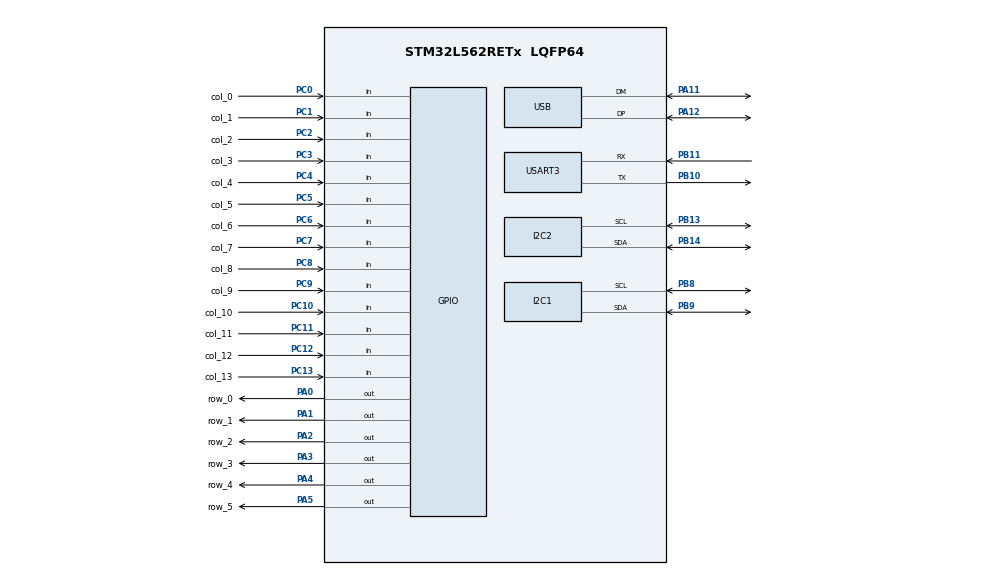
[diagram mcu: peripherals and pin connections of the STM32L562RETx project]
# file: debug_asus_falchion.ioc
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I2C1.Timing=0x10B0DCFB
I2C2.Timing=0x10B0DCFB
Mcu.Family=STM32L5
Mcu.Name=STM32L562RETx
Mcu.Package=LQFP64
NVIC.PriorityGroup=NVIC_PRIORITYGROUP_3
NVIC.USB_FS_IRQn=true\:0\:0\:false\:false\:true\:false\:true\:true
PA0.GPIO_Label=row_0
PA0.Signal=GPIO_Output
PA1.GPIO_Label=row_1
PA1.Signal=GPIO_Output
PA11.Mode=Device
PA11.Signal=USB_DM
PA12.Mode=Device
PA12.Signal=USB_DP
PA13\ (JTMS/SWDIO).Mode=Serial_Wire
PA13\ (JTMS/SWDIO).Signal=DEBUG_JTMS-SWDIO
PA14\ (JTCK/SWCLK).Mode=Serial_Wire
PA14\ (JTCK/SWCLK).Signal=DEBUG_JTCK-SWCLK
PA2.GPIO_Label=row_2
PA2.Signal=GPIO_Output
PA3.GPIO_Label=row_3
PA3.Signal=GPIO_Output
PA4.GPIO_Label=row_4
PA4.Signal=GPIO_Output
PA5.GPIO_Label=row_5
PA5.Signal=GPIO_Output
PB10.Mode=Asynchronous
PB10.Signal=USART3_TX
PB11.Mode=Asynchronous
PB11.Signal=USART3_RX
PB12.GPIO_Label=matrix
PB12.Signal=EVENTOUT
PB13.Mode=I2C
PB13.Signal=I2C2_SCL
PB14.Mode=I2C
PB14.Signal=I2C2_SDA
PB8.Mode=I2C
PB8.Signal=I2C1_SCL
PB9.Mode=I2C
PB9.Signal=I2C1_SDA
PC0.GPIO_Label=col_0
PC0.Signal=GPIO_Input
PC1.GPIO_Label=col_1
PC1.Signal=GPIO_Input
PC10.GPIO_Label=col_10
PC10.Signal=GPIO_Input
PC11.GPIO_Label=col_11
PC11.Signal=GPIO_Input
PC12.GPIO_Label=col_12
PC12.Signal=GPIO_Input
PC13.GPIO_Label=col_13
PC13.Signal=GPIO_Input
PC15-OSC32_OUT\ (PC15).GPIO_Label=reset radio
PC15-OSC32_OUT\ (PC15).Signal=EVENTOUT
PC2.GPIO_Label=col_2
PC2.Signal=GPIO_Input
PC3.GPIO_Label=col_3
PC3.Signal=GPIO_Input
PC4.GPIO_Label=col_4
PC4.Signal=GPIO_Input
PC5.GPIO_Label=col_5
PC5.Signal=GPIO_Input
PC6.GPIO_Label=col_6
PC6.Signal=GPIO_Input
PC7.GPIO_Label=col_7
PC7.Signal=GPIO_Input
PC8.GPIO_Label=col_8
PC8.Signal=GPIO_Input
PC9.GPIO_Label=col_9
PC9.Signal=GPIO_Input
PH0-OSC_IN\ (PH0).Mode=HSE-External-Oscillator
PH0-OSC_IN\ (PH0).Signal=RCC_OSC_IN
PH1-OSC_OUT\ (PH1).Mode=HSE-External-Oscillator
PH1-OSC_OUT\ (PH1).Signal=RCC_OSC_OUT
ProjectManager.HeapSize=0x200
ProjectManager.StackSize=0x4000
ProjectManager.TargetToolchain=Makefile
RCC.ADCFreq_Value=48000000
RCC.AHBFreq_Value=96000000
RCC.APB1Freq_Value=96000000
RCC.APB1TimFreq_Value=96000000
RCC.APB2Freq_Value=96000000
RCC.APB2TimFreq_Value=96000000
RCC.CortexFreq_Value=96000000
RCC.HCLKFreq_Value=96000000
RCC.HSE_VALUE=32000000
RCC.HSI48_VALUE=48000000
RCC.HSI_VALUE=16000000
RCC.LSE_VALUE=32768
RCC.MSI_VALUE=4000000
RCC.PLLM=2
RCC.PLLN=12
RCC.PLLSAI1M=4
RCC.PLLSAI1N=12
RCC.PLLSAI1Source=RCC_PLLSAI1SOURCE_HSE
RCC.PLLSourceVirtual=RCC_PLLSOURCE_HSE
RCC.SYSCLKFreq_VALUE=96000000
RCC.SYSCLKSource=RCC_SYSCLKSOURCE_PLLCLK
RCC.USBFreq_Value=48000000
RCC.VCOOutputFreq_Value=192000000
USART3.VirtualMode-Asynchronous=VM_ASYNC
USB_DEVICE.CLASS_NAME_FS=CDC
USB_DEVICE.VirtualMode=Cdc
USB_DEVICE.VirtualModeFS=Cdc_FS
VP_ICACHE_VS_ICACHE.Mode=DirectMappedCache
VP_PWR_VS_DBSignals.Mode=DisableDeadBatterySignals
VP_PWR_VS_SECSignals.Mode=Security/Privilege
VP_USB_DEVICE_VS_USB_DEVICE_CDC_FS.Mode=CDC_FS
board=custom

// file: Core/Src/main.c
/* USER CODE BEGIN Header */
/**
  ******************************************************************************
  * @file           : main.c
  * @brief          : Main program body
  ******************************************************************************
  * @attention
  *
  * Copyright (c) 2023 STMicroelectronics.
  * All rights reserved.
  *
  * This software is licensed under terms that can be found in the LICENSE file
  * in the root directory of this software component.
  * If no LICENSE file comes with this software, it is provided AS-IS.
  *
  ******************************************************************************
  */
/* USER CODE END Header */
#include "main.h"
#include "usb_device.h"

I2C_HandleTypeDef hi2c1;
I2C_HandleTypeDef hi2c2;

UART_HandleTypeDef huart3;

void SystemClock_Config(void);
static void MX_GPIO_Init(void);
static void MX_I2C1_Init(void);
static void MX_I2C2_Init(void);
static void MX_USART3_UART_Init(void);
static void MX_ICACHE_Init(void);

/* USER CODE BEGIN 0 */
int _write(int file, char *ptr, int len) {
    static uint8_t rc = USBD_OK;

    do {
        rc = CDC_Transmit_FS((uint8_t*)ptr, len);
    } while (USBD_BUSY == rc);

    if (USBD_FAIL == rc) {
        /// NOTE: Should never reach here.
        /// TODO: Handle this error.
        return 0;
    }
    return len;
}

// int fputc(int ch, FILE *f)
// {
//     if(ch == '\n') {
//       uint8_t ret = '\r';
//       CDC_Transmit_FS(&ret, 1);
//     }
//     CDC_Transmit_FS((uint8_t*)&ch, 1);
//     return ch;
// }

/* USER CODE END 0 */

int main(void)
{

  /* MCU Configuration--------------------------------------------------------*/

  /* Reset of all peripherals, Initializes the Flash interface and the Systick. */
  HAL_Init();

  /* Configure the system clock */
  SystemClock_Config();

  /* Initialize all configured peripherals */
  MX_GPIO_Init();
  MX_I2C1_Init();
  MX_I2C2_Init();
  MX_USART3_UART_Init();
  MX_ICACHE_Init();
  MX_USB_Device_Init();
  /* USER CODE BEGIN 2 */
  HAL_Delay(2000);

  printf("\r\nStart !\r\n");
  IS31FL3737_init(161);
  IS31FL3737_init(191);

  shell_start();
  /* USER CODE END 2 */

  /* Infinite loop */
  while (1)
  {

    /* USER CODE BEGIN 3 */
    //printf("[main]Hello World! \r\n");
    printf("Hello World!\r\n");
    HAL_Delay(1000);
  }
  /* USER CODE END 3 */
}

void SystemClock_Config(void)
{
  RCC_OscInitTypeDef RCC_OscInitStruct = {0};
  RCC_ClkInitTypeDef RCC_ClkInitStruct = {0};

  /** Configure the main internal regulator output voltage
  */
  if (HAL_PWREx_ControlVoltageScaling(PWR_REGULATOR_VOLTAGE_SCALE1) != HAL_OK)
  {
    Error_Handler();
  }

  /** Initializes the RCC Oscillators according to the specified parameters
  * in the RCC_OscInitTypeDef structure.
  */
  RCC_OscInitStruct.OscillatorType = RCC_OSCILLATORTYPE_HSI|RCC_OSCILLATORTYPE_HSE;
  RCC_OscInitStruct.HSEState = RCC_HSE_ON;
  RCC_OscInitStruct.HSIState = RCC_HSI_ON;
  RCC_OscInitStruct.HSICalibrationValue = RCC_HSICALIBRATION_DEFAULT;
  RCC_OscInitStruct.PLL.PLLState = RCC_PLL_ON;
  RCC_OscInitStruct.PLL.PLLSource = RCC_PLLSOURCE_HSE;
  RCC_OscInitStruct.PLL.PLLM = 2;
  RCC_OscInitStruct.PLL.PLLN = 10;
  RCC_OscInitStruct.PLL.PLLP = RCC_PLLP_DIV7;
  RCC_OscInitStruct.PLL.PLLQ = RCC_PLLQ_DIV2;
  RCC_OscInitStruct.PLL.PLLR = RCC_PLLR_DIV2;
  if (HAL_RCC_OscConfig(&RCC_OscInitStruct) != HAL_OK)
  {
    Error_Handler();
  }

  /** Initializes the CPU, AHB and APB buses clocks
  */
  RCC_ClkInitStruct.ClockType = RCC_CLOCKTYPE_HCLK|RCC_CLOCKTYPE_SYSCLK
                              |RCC_CLOCKTYPE_PCLK1|RCC_CLOCKTYPE_PCLK2;
  RCC_ClkInitStruct.SYSCLKSource = RCC_SYSCLKSOURCE_PLLCLK;
  RCC_ClkInitStruct.AHBCLKDivider = RCC_SYSCLK_DIV1;
  RCC_ClkInitStruct.APB1CLKDivider = RCC_HCLK_DIV1;
  RCC_ClkInitStruct.APB2CLKDivider = RCC_HCLK_DIV1;

  if (HAL_RCC_ClockConfig(&RCC_ClkInitStruct, FLASH_LATENCY_3) != HAL_OK)
  {
    Error_Handler();
  }
}

static void MX_I2C1_Init(void)
{

  hi2c1.Instance = I2C1;
  hi2c1.Init.Timing = 0x00303D5B;
  hi2c1.Init.OwnAddress1 = 0;
  hi2c1.Init.AddressingMode = I2C_ADDRESSINGMODE_7BIT;
  hi2c1.Init.DualAddressMode = I2C_DUALADDRESS_DISABLE;
  hi2c1.Init.OwnAddress2 = 0;
  hi2c1.Init.OwnAddress2Masks = I2C_OA2_NOMASK;
  hi2c1.Init.GeneralCallMode = I2C_GENERALCALL_DISABLE;
  hi2c1.Init.NoStretchMode = I2C_NOSTRETCH_DISABLE;
  if (HAL_I2C_Init(&hi2c1) != HAL_OK)
  {
    Error_Handler();
  }

  /** Configure Analogue filter
  */
  if (HAL_I2CEx_ConfigAnalogFilter(&hi2c1, I2C_ANALOGFILTER_ENABLE) != HAL_OK)
  {
    Error_Handler();
  }

  /** Configure Digital filter
  */
  if (HAL_I2CEx_ConfigDigitalFilter(&hi2c1, 0) != HAL_OK)
  {
    Error_Handler();
  }

}

static void MX_I2C2_Init(void)
{

  hi2c2.Instance = I2C2;
  hi2c2.Init.Timing = 0x00303D5B;
  hi2c2.Init.OwnAddress1 = 0;
  hi2c2.Init.AddressingMode = I2C_ADDRESSINGMODE_7BIT;
  hi2c2.Init.DualAddressMode = I2C_DUALADDRESS_DISABLE;
  hi2c2.Init.OwnAddress2 = 0;
  hi2c2.Init.OwnAddress2Masks = I2C_OA2_NOMASK;
  hi2c2.Init.GeneralCallMode = I2C_GENERALCALL_DISABLE;
  hi2c2.Init.NoStretchMode = I2C_NOSTRETCH_DISABLE;
  if (HAL_I2C_Init(&hi2c2) != HAL_OK)
  {
    Error_Handler();
  }

  /** Configure Analogue filter
  */
  if (HAL_I2CEx_ConfigAnalogFilter(&hi2c2, I2C_ANALOGFILTER_ENABLE) != HAL_OK)
  {
    Error_Handler();
  }

  /** Configure Digital filter
  */
  if (HAL_I2CEx_ConfigDigitalFilter(&hi2c2, 0) != HAL_OK)
  {
    Error_Handler();
  }

}

static void MX_ICACHE_Init(void)
{

  /** Enable instruction cache in 1-way (direct mapped cache)
  */
  if (HAL_ICACHE_ConfigAssociativityMode(ICACHE_1WAY) != HAL_OK)
  {
    Error_Handler();
  }
  if (HAL_ICACHE_Enable() != HAL_OK)
  {
    Error_Handler();
  }

}

static void MX_USART3_UART_Init(void)
{

  huart3.Instance = USART3;
  huart3.Init.BaudRate = 115200;
  huart3.Init.WordLength = UART_WORDLENGTH_8B;
  huart3.Init.StopBits = UART_STOPBITS_1;
  huart3.Init.Parity = UART_PARITY_NONE;
  huart3.Init.Mode = UART_MODE_TX_RX;
  huart3.Init.HwFlowCtl = UART_HWCONTROL_NONE;
  huart3.Init.OverSampling = UART_OVERSAMPLING_16;
  huart3.Init.OneBitSampling = UART_ONE_BIT_SAMPLE_DISABLE;
  huart3.Init.ClockPrescaler = UART_PRESCALER_DIV1;
  huart3.AdvancedInit.AdvFeatureInit = UART_ADVFEATURE_NO_INIT;
  if (HAL_UART_Init(&huart3) != HAL_OK)
  {
    Error_Handler();
  }
  if (HAL_UARTEx_SetTxFifoThreshold(&huart3, UART_TXFIFO_THRESHOLD_1_8) != HAL_OK)
  {
    Error_Handler();
  }
  if (HAL_UARTEx_SetRxFifoThreshold(&huart3, UART_RXFIFO_THRESHOLD_1_8) != HAL_OK)
  {
    Error_Handler();
  }
  if (HAL_UARTEx_DisableFifoMode(&huart3) != HAL_OK)
  {
    Error_Handler();
  }

}

static void MX_GPIO_Init(void)
{
  GPIO_InitTypeDef GPIO_InitStruct = {0};

  /* GPIO Ports Clock Enable */
  __HAL_RCC_GPIOC_CLK_ENABLE();
  __HAL_RCC_GPIOH_CLK_ENABLE();
  __HAL_RCC_GPIOA_CLK_ENABLE();
  __HAL_RCC_GPIOB_CLK_ENABLE();

  /*Configure GPIO pin Output Level */
  HAL_GPIO_WritePin(GPIOA, row_0_Pin|row_1_Pin|row_2_Pin|row_3_Pin
                          |row_4_Pin|row_5_Pin, GPIO_PIN_RESET);

  HAL_GPIO_WritePin(GPIOB, matrix_Pin, GPIO_PIN_SET);

  /*Configure GPIO pins : col_13_Pin col_0_Pin col_1_Pin col_2_Pin
                           col_3_Pin col_4_Pin col_5_Pin col_6_Pin
                           col_7_Pin col_8_Pin col_9_Pin col_10_Pin
                           col_11_Pin col_12_Pin */
  GPIO_InitStruct.Pin = col_13_Pin|col_0_Pin|col_1_Pin|col_2_Pin
                          |col_3_Pin|col_4_Pin|col_5_Pin|col_6_Pin
                          |col_7_Pin|col_8_Pin|col_9_Pin|col_10_Pin
                          |col_11_Pin|col_12_Pin;
  GPIO_InitStruct.Mode = GPIO_MODE_INPUT;
  GPIO_InitStruct.Pull = GPIO_PULLDOWN;
  HAL_GPIO_Init(GPIOC, &GPIO_InitStruct);

  /*Configure GPIO pin : reset_radio_Pin */
  GPIO_InitStruct.Pin = reset_radio_Pin;
  GPIO_InitStruct.Mode = GPIO_MODE_INPUT;
  GPIO_InitStruct.Pull = GPIO_NOPULL;
  HAL_GPIO_Init(reset_radio_GPIO_Port, &GPIO_InitStruct);

  /*Configure GPIO pins : row_0_Pin row_1_Pin row_2_Pin row_3_Pin
                           row_4_Pin row_5_Pin */
  GPIO_InitStruct.Pin = row_0_Pin|row_1_Pin|row_2_Pin|row_3_Pin
                          |row_4_Pin|row_5_Pin;
  GPIO_InitStruct.Mode = GPIO_MODE_OUTPUT_PP;
  GPIO_InitStruct.Pull = GPIO_PULLDOWN;
  GPIO_InitStruct.Speed = GPIO_SPEED_FREQ_VERY_HIGH;
  HAL_GPIO_Init(GPIOA, &GPIO_InitStruct);

  /*Configure GPIO pin : matrix_Pin */
  GPIO_InitStruct.Pin = matrix_Pin;
  GPIO_InitStruct.Mode = GPIO_MODE_OUTPUT_PP;
  GPIO_InitStruct.Pull = GPIO_PULLUP;
  GPIO_InitStruct.Speed = GPIO_SPEED_FREQ_VERY_HIGH;
  HAL_GPIO_Init(matrix_GPIO_Port, &GPIO_InitStruct);

}

void Error_Handler(void)
{
  __disable_irq();
  while (1)
  {
  }
}
